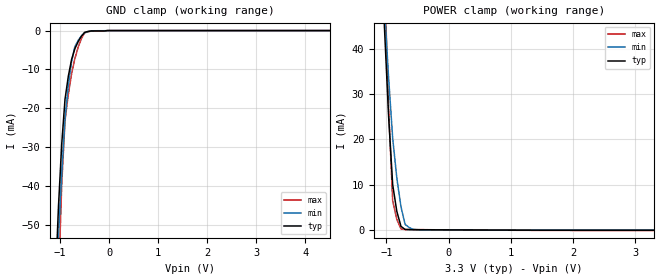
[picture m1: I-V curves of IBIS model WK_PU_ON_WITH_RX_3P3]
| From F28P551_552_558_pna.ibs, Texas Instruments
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|OPEN_DRAIN_MODE_3P3
|   Model Cell WK_PU_ON_WITH_RX_3P3
|WK_PU_ON_WITH_RX_3P3
[Model]   WK_PU_ON_WITH_RX_3P3
Model_type   Input
Polarity   Non-Inverting
Vinl =  0.8
Vinh =  2
C_comp   1.11773p   1.013376p   1.244487p
[Model Spec]
Vinl   0.8   0.8   0.8
Vinh   2   2   2
[Temperature Range]   25   155   -40
[Voltage Range]   3.3   2.97   3.63
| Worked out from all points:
|   GND clamp passes 1 mA (typ) near -0.54 V on its own axis
|   POWER clamp passes 1 mA (typ) near -0.77 V on its own axis
| Nom Voltages:
|   BIASFET=3.3, VDD=1.2, VDDS=3.3, VSS=0
| Min Voltages:
|   BIASFET=2.97, VDD=1.08, VDDS=2.97, VSS=0
| Max Voltages:
|   BIASFET=3.63, VDD=1.32, VDDS=3.63, VSS=0
[POWER_clamp]
|   voltage   I(typ)   I(min)   I(max)
-3.3V     1.132A     1.059A     1.769A
-1.033V   45.08mA    49.59mA    56.93mA
-966.7mV  25.39mA    33.9mA     27.23mA
-900mV    10.01mA    20.29mA    6.454mA
-833.3mV  4.092mA    11.48mA    2.326mA
-766.7mV  785.4uA    5.125mA    201.1uA
-700mV    89.29uA    1.212mA    78.7uA
-633.3mV  61.2uA     494uA      69.62uA
-566.7mV  44.07uA    99.73uA    61.24uA
3.3V      -85.93uA   -55.95uA   -137.9uA
[GND_clamp]
|   voltage   I(typ)   I(min)   I(max)
-3.3V     -1.198A    -966mA     -2.548A
-1.1V     -66.27mA   -70.87mA   -99.83mA
-1.033V   -45.41mA   -52.93mA   -65.12mA
-966.7mV  -29.23mA   -36.93mA   -39.6mA
-900mV    -17.72mA   -22.86mA   -23.27mA
-833.3mV  -11.83mA   -14.27mA   -16.55mA
-766.7mV  -7.493mA   -8.038mA   -11.21mA
-700mV    -4.704mA   -4.168mA   -7.263mA
-566.7mV  -1.465mA   -1.376mA   -2.095mA
-500mV    -469.8uA   -575.8uA   -591.3uA
-33.33mV  0A         0A         0A
6.6V      0A         0A         0A
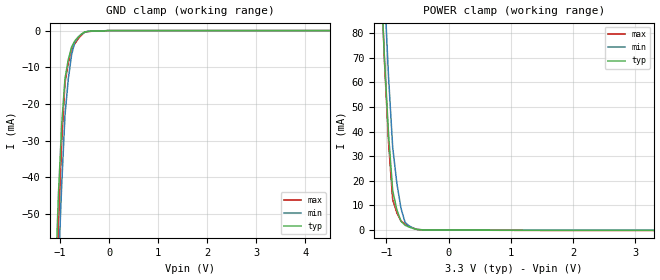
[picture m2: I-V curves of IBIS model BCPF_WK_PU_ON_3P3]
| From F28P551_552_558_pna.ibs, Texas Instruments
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|BCPF_WK_PD_ON_3P3; WEAK_PULLDOWN_ON
|   Model Cell BCPF_WK_PU_ON_3P3
|BCPF_WK_PU_ON_3P3
[Model]   BCPF_WK_PU_ON_3P3
Model_type   Input
Polarity   Non-Inverting
Vinl =  0.8
Vinh =  2
C_comp   1.21982p   0.982413p   1.3757p
[Model Spec]
Vinl   0.8   0.8   0.8
Vinh   2   2   2
[Temperature Range]   25   155   -40
[Voltage Range]   3.3   2.97   3.63
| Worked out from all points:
|   GND clamp passes 1 mA (typ) near -0.57 V on its own axis
|   POWER clamp passes 1 mA (typ) near -0.61 V on its own axis
| Nom Voltages:
|   BIASFET=3.3, VDD=1.2, VDDS=3.3, VSS=0
| Min Voltages:
|   BIASFET=2.97, VDD=1.08, VDDS=2.97, VSS=0
| Max Voltages:
|   BIASFET=3.63, VDD=1.32, VDDS=3.63, VSS=0
[POWER_clamp]
|   voltage   I(typ)   I(min)   I(max)
-3.3V     1.919A     2.431A     2.069A
-1.1V     109.8mA    140.8mA    113.2mA
-1.033V   70.21mA    98.04mA    69.24mA
-966.7mV  38.95mA    62.35mA    35.63mA
-900mV    16.03mA    33.73mA    12.36mA
-833.3mV  8.266mA    19.09mA    7.029mA
-766.7mV  3.571mA    8.879mA    3.722mA
-700mV    1.939mA    3.079mA    2.444mA
-566.7mV  603.9uA    711.2uA    759.2uA
-500mV    195.8uA    269.7uA    227.2uA
-366.7mV  40.85uA    44.56uA    53.2uA
3.3V      -108.8uA   -62.99uA   -174uA
[GND_clamp]
|   voltage   I(typ)   I(min)   I(max)
-3.3V     -1.48A     -1.41A     -2.182A
-1.1V     -69.91mA   -89.89mA   -82.68mA
-1.033V   -44.46mA   -64.18mA   -52.64mA
-966.7mV  -25.52mA   -41.89mA   -29.83mA
-900mV    -13.08mA   -23mA      -14.24mA
-833.3mV  -7.945mA   -13.29mA   -8.83mA
-766.7mV  -4.523mA   -6.66mA    -5.269mA
-700mV    -2.817mA   -3.105mA   -3.556mA
-566.7mV  -980.5uA   -1.002mA   -1.249mA
-500mV    -376.2uA   -438.1uA   -476.5uA
-33.33mV  0A         0A         0A
6.6V      0A         0A         0A
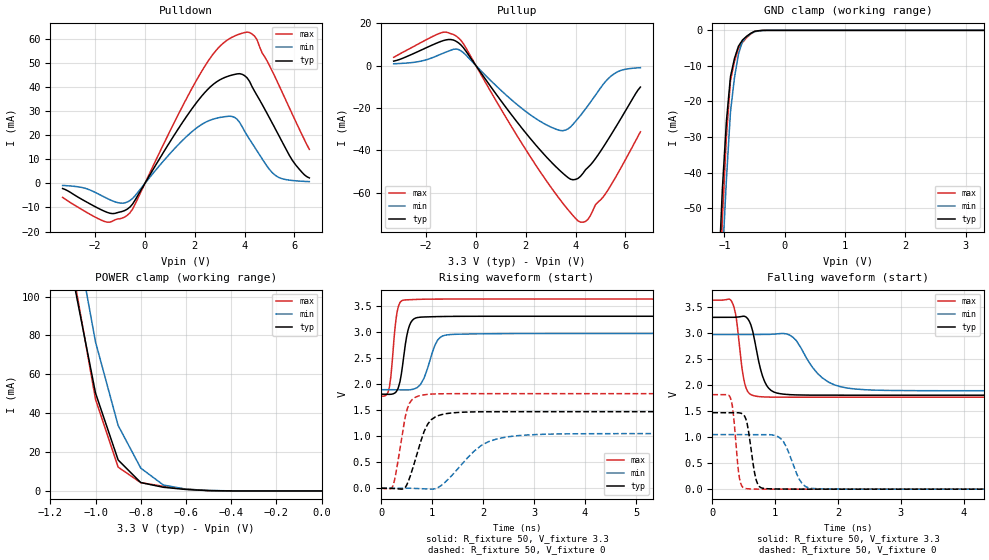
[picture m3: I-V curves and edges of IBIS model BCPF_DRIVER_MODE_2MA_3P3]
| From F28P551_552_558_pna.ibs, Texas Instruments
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|   Model Cell BCPF_DRIVER_MODE_2MA_3P3
|BCPF_DRIVER_MODE_2MA_3P3
[Model]   BCPF_DRIVER_MODE_2MA_3P3
Model_type   I/O
Polarity   Non-Inverting
Enable   Active-Low
Vinl =  0.8
Vinh =  2
Cref =  15.0000pF
Rref =  100.0000M
Vref =  0V
Vmeas =  1.65
C_comp   1.21982p   0.982413p   1.3757p
[Model Spec]
Vinl   0.8   0.8   0.8
Vinh   2   2   2
[Temperature Range]   25   155   -40
[Voltage Range]   3.3   2.97   3.63
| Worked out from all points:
|   slope of the pulldown table from 0 to 0.495 V, typ, clamps not added: 57.1 ohm
|   slope of the pullup table from 0 to 0.495 V, typ, clamps not added: 59.6 ohm
|   GND clamp passes 1 mA (typ) near -0.58 V on its own axis
|   POWER clamp passes 1 mA (typ) near -0.62 V on its own axis
|   rising waveform, R_fixture 50, V_fixture 3.3: 20-80 % time 140ps typ, 221ps min, 104ps max; typ from 1.8 V to 3.3 V
|   rising waveform, R_fixture 50, V_fixture 0: 20-80 % time 294ps typ, 647ps min, 192ps max; typ from 0 V to 1.47 V
|   falling waveform, R_fixture 50, V_fixture 3.3: 20-80 % time 172ps typ, 397ps min, 112ps max; typ from 3.3 V to 1.8 V
|   falling waveform, R_fixture 50, V_fixture 0: 20-80 % time 109ps typ, 211ps min, 80.2ps max; typ from 1.47 V to 0 V
| Nom Voltages:
|   BIASFET=3.3, VDD=1.2, VDDS=3.3, VSS=0
| Min Voltages:
|   BIASFET=2.97, VDD=1.08, VDDS=2.97, VSS=0
| Max Voltages:
|   BIASFET=3.63, VDD=1.32, VDDS=3.63, VSS=0
[POWER_clamp]
|   voltage   I(typ)   I(min)   I(max)
-3.3V     1.919A     2.431A     2.069A
-1.1V     109.8mA    140.8mA    113.1mA
-1.067V   89.98mA    119.4mA    91.15mA
-1.033V   70.17mA    98.03mA    69.15mA
-1V       50.36mA    76.65mA    47.16mA
-900mV    15.95mA    33.71mA    12.25mA
-800mV    4.313mA    11.75mA    4.256mA
-700mV    1.873mA    3.047mA    2.352mA
-600mV    751.5uA    902uA      945.8uA
-500mV    149.1uA    244.6uA    161.3uA
0V        284.5pA    4.537nA    258.9pA
[Pulldown]
|   voltage   I(typ)   I(min)   I(max)
-3.3V     -2.106mA   -829.9uA   -5.795mA
-1.6V     -11.66mA   -5.789mA   -15.87mA
-700mV    -10.64mA   -7.705mA   -13.21mA
-400mV    -7.072mA   -5.205mA   -8.811mA
1.4V      23.67mA    16.77mA    29.91mA
2.4V      37.79mA    25.3mA     48.71mA
3.5V      45.14mA    27.89mA    60.88mA
4.1V      44.01mA    20.04mA    63.01mA
4.5V      36.67mA    13.59mA    59.86mA
5.2V      23.42mA    3.673mA    44.88mA
5.9V      9.948mA    1.257mA    29.22mA
6.6V      2.302mA    773.2uA    14.19mA
[Pullup]
|   voltage   I(typ)   I(min)   I(max)
-3.3V     2.084mA    839.6uA    3.878mA
-1.4V     11.4mA     5.387mA    15.44mA
-700mV    10.72mA    7.564mA    13.05mA
1.5V      -24.35mA   -16.9mA    -30.22mA
2.8V      -42.78mA   -27.82mA   -53.93mA
3.6V      -51.98mA   -30.47mA   -66.68mA
3.9V      -53.94mA   -27.71mA   -70.9mA
4.2V      -52.27mA   -23.51mA   -73.96mA
4.5V      -48.09mA   -18.87mA   -72.58mA
4.8V      -43.92mA   -13.95mA   -65.69mA
5.4V      -33.13mA   -5.221mA   -56.87mA
6.6V      -10.17mA   -1.007mA   -31.3mA
[GND_clamp]
|   voltage   I(typ)   I(min)   I(max)
-3.3V     -1.48A     -1.41A     -2.182A
-1.1V     -69.89mA   -89.88mA   -82.66mA
-1.033V   -44.44mA   -64.17mA   -52.62mA
-966.7mV  -25.49mA   -41.87mA   -29.79mA
-900mV    -13.05mA   -22.99mA   -14.19mA
-833.3mV  -7.883mA   -13.27mA   -8.716mA
-766.7mV  -4.439mA   -6.634mA   -5.116mA
-700mV    -2.713mA   -3.07mA    -3.386mA
-566.7mV  -872.3uA   -953.1uA   -1.075mA
-500mV    -267.3uA   -387.3uA   -301.7uA
-300mV    -620.6nA   -5.397uA   -306.5nA
3.3V      284.5pA    7.662uA    205pA
[Ramp]
| variable   typ   min   max
dV/dt_f 0.91068086/0.17315914n 0.65955626/0.40063246n  1.1310004/0.11316852n
dV/dt_r 0.89181332/0.29713445n 0.63958487/0.65404172n  1.0978302/0.1928678n
R_load = 50
[Rising Waveform]
R_fixture = 50
V_fixture = 3.3
V_fixture_min = 2.97
V_fixture_max = 3.63
|   time   V(typ)   V(min)   V(max)
0s        1.805V     1.891V     1.767V
159.2ps   1.802V     1.891V     1.943V
276.6ps   1.837V     1.89V      3.145V
328.2ps   1.912V     1.889V     3.461V
472.6ps   2.765V     1.885V     3.614V
643.6ps   3.252V     1.905V     3.621V
841.1ps   3.286V     2.117V     3.627V
1.107ns   3.294V     2.844V     3.63V
1.375ns   3.298V     2.95V      3.63V
20.05ns   3.3V       2.97V      3.63V
[Rising Waveform]
R_fixture = 50
V_fixture = 0
V_fixture_min = 0
V_fixture_max = 0
|   time   V(typ)   V(min)   V(max)
0s        0V         0V         0V
184.2ps   0V         0V         -11.16mV
237ps     -4.349mV   0V         69.12mV
472.8ps   19.15mV    0V         1.38V
596.4ps   317.8mV    0V         1.693V
883.4ps   1.177V     -13.59mV   1.799V
1.17ns    1.409V     49.43mV    1.813V
1.96ns    1.467V     819.3mV    1.815V
2.852ns   1.469V     1.022V     1.815V
20.01ns   1.469V     1.048V     1.815V
[Falling Waveform]
R_fixture = 50
V_fixture = 3.3
V_fixture_min = 2.97
V_fixture_max = 3.63
|   time   V(typ)   V(min)   V(max)
0s        3.3V       2.97V      3.63V
325.7ps   3.3V       2.97V      3.557V
496.2ps   3.323V     2.97V      2.133V
562.6ps   3.274V     2.97V      1.875V
788.2ps   2.213V     2.97V      1.773V
1.061ns   1.837V     2.987V     1.767V
1.284ns   1.812V     2.916V     1.766V
1.847ns   1.805V     2.056V     1.767V
2.418ns   1.805V     1.911V     1.767V
20.05ns   1.805V     1.891V     1.767V
[Falling Waveform]
R_fixture = 50
V_fixture = 0
V_fixture_min = 0
V_fixture_max = 0
|   time   V(typ)   V(min)   V(max)
0s        1.469V     1.048V     1.815V
284.2ps   1.469V     1.048V     1.765V
333.9ps   1.47V      1.048V     1.447V
433.4ps   1.465V     1.048V     195.6mV
577.2ps   1.097V     1.049V     5.968mV
697.4ps   174.8mV    1.049V     0V
894.6ps   7.295mV    1.048V     0V
1.09ns    2.604mV    969.1mV    0V
1.63ns    0V         9.869mV    0V
20.01ns   0V         0V         0V
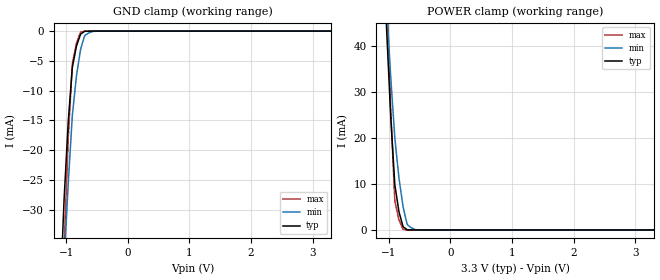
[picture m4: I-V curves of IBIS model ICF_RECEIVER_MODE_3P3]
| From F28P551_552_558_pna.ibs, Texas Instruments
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|ICF_WK_PD_ON_3P3; WEAK_PULLDOWN_ON
|   Model Cell ICF_RECEIVER_MODE_3P3
|ICF_RECEIVER_MODE_3P3
[Model]   ICF_RECEIVER_MODE_3P3
Model_type   Input
Polarity   Non-Inverting
Vinl =  0.8
Vinh =  2
C_comp   0.705929p   0.524756p   0.819798p
[Model Spec]
Vinl   0.8   0.8   0.8
Vinh   2   2   2
[Temperature Range]   25   155   -40
[Voltage Range]   3.3   2.97   3.63
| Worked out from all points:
|   GND clamp passes 1 mA (typ) near -0.78 V on its own axis
|   POWER clamp passes 1 mA (typ) near -0.77 V on its own axis
| Nom Voltages:
|   BIASFET=3.3, VDD=1.2, VDDS=3.3, VSS=0
| Min Voltages:
|   BIASFET=2.97, VDD=1.08, VDDS=2.97, VSS=0
| Max Voltages:
|   BIASFET=3.63, VDD=1.32, VDDS=3.63, VSS=0
[POWER_clamp]
|   voltage   I(typ)   I(min)   I(max)
-3.3V     1.081A     1.025A     1.649A
-1.033V   43.59mA    48.4mA     54mA
-966.7mV  24.68mA    33.19mA    26.05mA
-900mV    9.809mA    19.96mA    6.269mA
-833.3mV  3.983mA    11.32mA    2.208mA
-766.7mV  725.6uA    5.059mA    119.3uA
-700mV    36.21uA    1.184mA    3.804uA
-633.3mV  13.05uA    468.6uA    1.632uA
-566.7mV  1.004uA    77.01uA    376.5nA
3.3V      -122.3pA   -178.5nA   -103.6pA
[GND_clamp]
|   voltage   I(typ)   I(min)   I(max)
-3.3V     -921.9mA   -819.9mA   -1.722A
-1.1V     -45.04mA   -53.69mA   -60.94mA
-1.033V   -28.27mA   -38.87mA   -36.58mA
-966.7mV  -15.3mA    -25.7mA    -18.11mA
-900mV    -6.119mA   -14.19mA   -5.524mA
-833.3mV  -2.544mA   -7.576mA   -2.031mA
-766.7mV  -516.7uA   -3.097mA   -192.4uA
-700mV    -37.6uA    -751uA     -9.113uA
-566.7mV  -1.793uA   -61.77uA   -1.3uA
-500mV    -316.1nA   -8.977uA   -253.9nA
3.3V      210.2pA    137.5nA    178.6pA
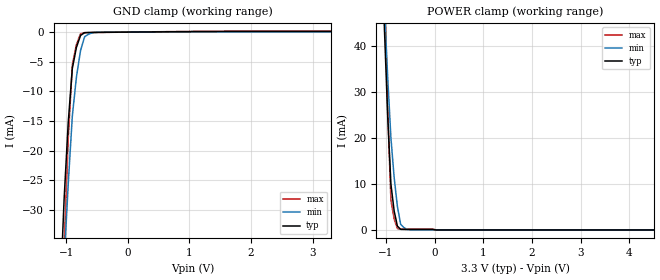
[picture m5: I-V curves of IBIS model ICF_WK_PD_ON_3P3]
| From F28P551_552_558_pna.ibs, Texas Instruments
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|   Model Cell ICF_WK_PD_ON_3P3
|ICF_WK_PD_ON_3P3
[Model]   ICF_WK_PD_ON_3P3
Model_type   Input
Polarity   Non-Inverting
Vinl =  0.8
Vinh =  2
C_comp   0.705929p   0.524756p   0.819798p
[Model Spec]
Vinl   0.8   0.8   0.8
Vinh   2   2   2
[Temperature Range]   25   155   -40
[Voltage Range]   3.3   2.97   3.63
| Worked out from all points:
|   GND clamp passes 1 mA (typ) near -0.78 V on its own axis
|   POWER clamp passes 1 mA (typ) near -0.77 V on its own axis
| Nom Voltages:
|   BIASFET=3.3, VDD=1.2, VDDS=3.3, VSS=0
| Min Voltages:
|   BIASFET=2.97, VDD=1.08, VDDS=2.97, VSS=0
| Max Voltages:
|   BIASFET=3.63, VDD=1.32, VDDS=3.63, VSS=0
[POWER_clamp]
|   voltage   I(typ)   I(min)   I(max)
-3.3V     1.081A     1.025A     1.649A
-1.033V   43.65mA    48.41mA    54.13mA
-966.7mV  24.75mA    33.21mA    26.21mA
-900mV    9.902mA    19.98mA    6.441mA
-833.3mV  4.083mA    11.35mA    2.383mA
-766.7mV  830uA      5.098mA    296uA
-700mV    141.9uA    1.23mA     181.2uA
-633.3mV  119.3uA    517.3uA    179.8uA
-566.7mV  107.7uA    127.2uA    179.1uA
-500mV    107.1uA    59.96uA    178.9uA
33.33mV   0A         0A         0A
6.6V      0A         0A         0A
[GND_clamp]
|   voltage   I(typ)   I(min)   I(max)
-3.3V     -921.9mA   -819.9mA   -1.722A
-1.1V     -45.05mA   -53.69mA   -60.95mA
-1.033V   -28.29mA   -38.87mA   -36.59mA
-966.7mV  -15.32mA   -25.71mA   -18.12mA
-900mV    -6.141mA   -14.2mA    -5.548mA
-833.3mV  -2.58mA    -7.589mA   -2.09mA
-766.7mV  -565uA     -3.114mA   -273.6uA
-700mV    -96.68uA   -773.5uA   -98.02uA
-566.7mV  -52.72uA   -88.84uA   -76.49uA
-500mV    -45.74uA   -34.15uA   -67.39uA
3.3V      106.7uA    51.11uA    177.8uA
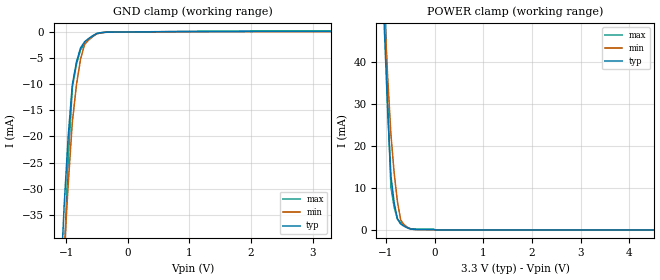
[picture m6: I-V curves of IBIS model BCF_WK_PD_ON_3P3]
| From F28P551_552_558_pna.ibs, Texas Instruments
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|   Model Cell BCF_WK_PD_ON_3P3
|BCF_WK_PD_ON_3P3
[Model]   BCF_WK_PD_ON_3P3
Model_type   Input
Polarity   Non-Inverting
Vinl =  0.8
Vinh =  2
C_comp   1.28683p   1.00698p   1.46241p
[Model Spec]
Vinl   0.8   0.8   0.8
Vinh   2   2   2
[Temperature Range]   25   155   -40
[Voltage Range]   3.3   2.97   3.63
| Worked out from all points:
|   GND clamp passes 1 mA (typ) near -0.60 V on its own axis
|   POWER clamp passes 1 mA (typ) near -0.65 V on its own axis
| Nom Voltages:
|   BIASFET=3.3, VDD=1.2, VDDS=3.3, VSS=0
| Min Voltages:
|   BIASFET=2.97, VDD=1.08, VDDS=2.97, VSS=0
| Max Voltages:
|   BIASFET=3.63, VDD=1.32, VDDS=3.63, VSS=0
[POWER_clamp]
|   voltage   I(typ)   I(min)   I(max)
-3.3V     1.107A     1.023A     1.677A
-1.033V   47.42mA    52.06mA    58.71mA
-966.7mV  28.13mA    36.41mA    30.42mA
-900mV    12.85mA    22.7mA     10.2mA
-833.3mV  6.476mA    13.54mA    5.424mA
-766.7mV  2.66mA     6.776mA    2.62mA
-700mV    1.404mA    2.41mA     1.782mA
-566.7mV  517.2uA    574.5uA    683.4uA
-500mV    228.9uA    248.6uA    311.4uA
-366.7mV  112.5uA    73.48uA    183.4uA
33.33mV   0A         0A         0A
6.6V      0A         0A         0A
[GND_clamp]
|   voltage   I(typ)   I(min)   I(max)
-3.3V     -944.5mA   -826.8mA   -1.736A
-1.1V     -50.7mA    -57.86mA   -68.89mA
-1.033V   -33.48mA   -42.7mA    -43.82mA
-966.7mV  -19.95mA   -29.18mA   -24.41mA
-900mV    -10.1mA    -17.28mA   -10.65mA
-833.3mV  -5.796mA   -10.18mA   -6.165mA
-766.7mV  -3.052mA   -5.196mA   -3.386mA
-700mV    -1.868mA   -2.325mA   -2.314mA
-566.7mV  -694uA     -751.1uA   -858.4uA
-500mV    -270.4uA   -343.4uA   -322uA
-300mV    -27.35uA   -20.01uA   -40.48uA
3.3V      105.9uA    57.28uA    177.6uA
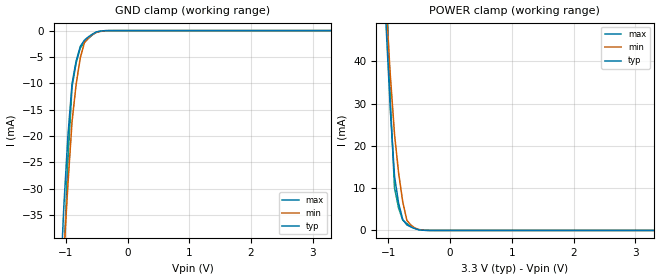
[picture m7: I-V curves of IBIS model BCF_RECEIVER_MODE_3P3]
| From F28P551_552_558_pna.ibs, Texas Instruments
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|   Model Cell BCF_RECEIVER_MODE_3P3
|BCF_RECEIVER_MODE_3P3
[Model]   BCF_RECEIVER_MODE_3P3
Model_type   Input
Polarity   Non-Inverting
Vinl =  0.8
Vinh =  2
C_comp   1.28683p   1.00698p   1.46241p
[Model Spec]
Vinl   0.8   0.8   0.8
Vinh   2   2   2
[Temperature Range]   25   155   -40
[Voltage Range]   3.3   2.97   3.63
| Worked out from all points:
|   GND clamp passes 1 mA (typ) near -0.61 V on its own axis
|   POWER clamp passes 1 mA (typ) near -0.66 V on its own axis
| Nom Voltages:
|   BIASFET=3.3, VDD=1.2, VDDS=3.3, VSS=0
| Min Voltages:
|   BIASFET=2.97, VDD=1.08, VDDS=2.97, VSS=0
| Max Voltages:
|   BIASFET=3.63, VDD=1.32, VDDS=3.63, VSS=0
[POWER_clamp]
|   voltage   I(typ)   I(min)   I(max)
-3.3V     1.107A     1.023A     1.677A
-1.033V   47.37mA    52.05mA    58.58mA
-966.7mV  28.06mA    36.39mA    30.27mA
-900mV    12.76mA    22.68mA    10.02mA
-833.3mV  6.376mA    13.51mA    5.25mA
-766.7mV  2.556mA    6.737mA    2.444mA
-700mV    1.299mA    2.365mA    1.605mA
-633.3mV  803.5uA    1.247mA    995.7uA
-566.7mV  411.4uA    524.7uA    505.1uA
-500mV    122.7uA    198.2uA    132.8uA
-366.7mV  6.325uA    22.93uA    4.864uA
3.3V      -325.7pA   -11.09uA   -316.3pA
[GND_clamp]
|   voltage   I(typ)   I(min)   I(max)
-3.3V     -944.5mA   -826.8mA   -1.736A
-1.1V     -50.69mA   -57.85mA   -68.88mA
-1.033V   -33.47mA   -42.7mA    -43.81mA
-966.7mV  -19.93mA   -29.17mA   -24.39mA
-900mV    -10.08mA   -17.27mA   -10.63mA
-833.3mV  -5.761mA   -10.17mA   -6.106mA
-766.7mV  -3.004mA   -5.18mA    -3.306mA
-700mV    -1.81mA    -2.303mA   -2.225mA
-566.7mV  -643.8uA   -724.5uA   -783.6uA
-500mV    -225.6uA   -318.6uA   -255.2uA
-300mV    -598.1nA   -5.157uA   -296.9nA
3.3V      319.4pA    6.726uA    227.5pA
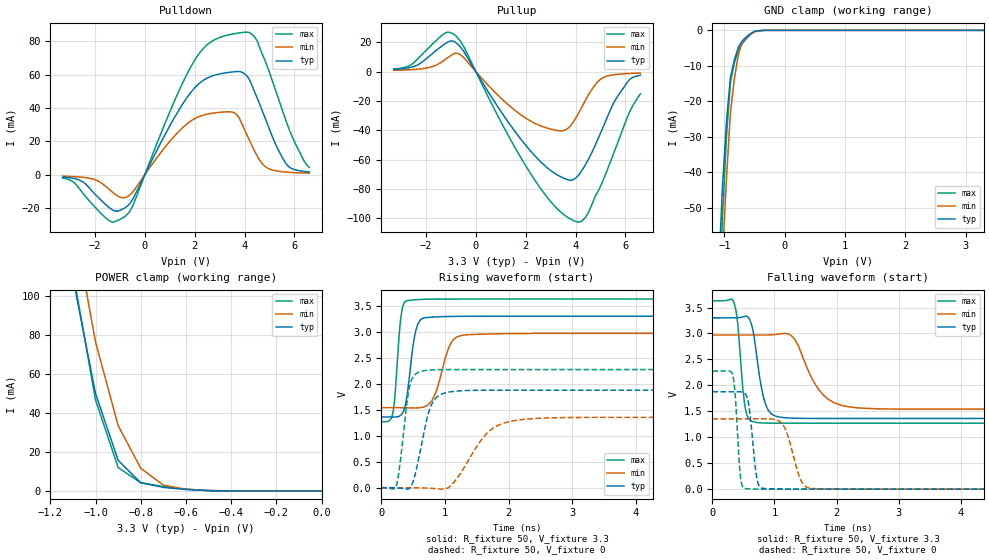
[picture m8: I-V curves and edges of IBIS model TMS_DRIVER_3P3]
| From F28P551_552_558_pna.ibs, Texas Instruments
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|   Model Cell TMS_DRIVER_3P3
|TMS_DRIVER_3P3
[Model]   TMS_DRIVER_3P3
Model_type   I/O
Polarity   Non-Inverting
Enable   Active-Low
Vinl =  0.8
Vinh =  2
Cref =  15.0000pF
Rref =  100.0000M
Vref =  0V
Vmeas =  1.65
C_comp   1.26765p   1.03155p   1.45072p
[Model Spec]
Vinl   0.8   0.8   0.8
Vinh   2   2   2
[Temperature Range]   25   155   -40
[Voltage Range]   3.3   2.97   3.63
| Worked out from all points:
|   slope of the pulldown table from 0 to 0.495 V, typ, clamps not added: 33.1 ohm
|   slope of the pullup table from 0 to 0.495 V, typ, clamps not added: 35.9 ohm
|   GND clamp passes 1 mA (typ) near -0.57 V on its own axis
|   POWER clamp passes 1 mA (typ) near -0.63 V on its own axis
|   rising waveform, R_fixture 50, V_fixture 3.3: 20-80 % time 122ps typ, 203ps min, 84.7ps max; typ from 1.36 V to 3.3 V
|   rising waveform, R_fixture 50, V_fixture 0: 20-80 % time 203ps typ, 451ps min, 131ps max; typ from 0 V to 1.88 V
|   falling waveform, R_fixture 50, V_fixture 3.3: 20-80 % time 154ps typ, 366ps min, 98.3ps max; typ from 3.3 V to 1.36 V
|   falling waveform, R_fixture 50, V_fixture 0: 20-80 % time 95ps typ, 193ps min, 68.9ps max; typ from 1.88 V to 0 V
| Nom Voltages:
|   BIASFET=3.3, VDD=1.2, VDDS=3.3, VSS=0
| Min Voltages:
|   BIASFET=2.97, VDD=1.08, VDDS=2.97, VSS=0
| Max Voltages:
|   BIASFET=3.63, VDD=1.32, VDDS=3.63, VSS=0
[POWER_clamp]
|   voltage   I(typ)   I(min)   I(max)
-3.3V     1.919A     2.431A     2.069A
-1.1V     109.6mA    140.7mA    112.7mA
-1.067V   89.74mA    119.3mA    90.7mA
-1.033V   69.92mA    97.93mA    68.74mA
-1V       50.1mA     76.55mA    46.78mA
-900mV    15.74mA    33.61mA    12.02mA
-800mV    4.204mA    11.66mA    4.167mA
-700mV    1.814mA    2.972mA    2.293mA
-600mV    716.5uA    858.2uA    909.7uA
-500mV    138.9uA    227uA      152.2uA
0V        307.5pA    4.709nA    280.9pA
[Pulldown]
|   voltage   I(typ)   I(min)   I(max)
-3.3V     -1.487mA   -924.2uA   -2.099mA
-2.5V     -4.195mA   -1.617mA   -10.9mA
-1.4V     -20.16mA   -9.286mA   -27.98mA
-800mV    -19.96mA   -13.84mA   -25.2mA
-500mV    -15.16mA   -10.67mA   -19.2mA
1.1V      31.93mA    21.68mA    41.17mA
2.1V      53.66mA    34.39mA    71.06mA
3.5V      61.62mA    37.57mA    84.37mA
4.1V      59.16mA    23.66mA    85.59mA
4.5V      46.26mA    11.37mA    80.54mA
5.6V      8.041mA    1.603mA    35.1mA
6.6V      1.614mA    875.6uA    4.352mA
[Pullup]
|   voltage   I(typ)   I(min)   I(max)
-3.3V     1.549mA    921.4uA    1.826mA
-2.6V     3.01mA     1.383mA    4.759mA
-1.8V     11.56mA    3.248mA    17.91mA
-900mV    20.89mA    12.19mA    25.83mA
-500mV    14.17mA    9.801mA    17.58mA
2.4V      -58.06mA   -35.54mA   -74.92mA
3.5V      -72.55mA   -40.3mA    -97.22mA
4.1V      -71.09mA   -28.89mA   -102.8mA
4.4V      -63.3mA    -19.35mA   -99.38mA
5V        -41.98mA   -5.171mA   -78.29mA
5.8V      -13.95mA   -1.597mA   -43.52mA
6.6V      -2.434mA   -958.5uA   -15.11mA
[GND_clamp]
|   voltage   I(typ)   I(min)   I(max)
-3.3V     -1.48A     -1.41A     -2.182A
-1.1V     -69.78mA   -89.94mA   -82.82mA
-1.033V   -44.53mA   -64.24mA   -52.89mA
-966.7mV  -25.7mA    -41.95mA   -30.12mA
-900mV    -13.3mA    -23.09mA   -14.49mA
-833.3mV  -8.122mA   -13.37mA   -9.07mA
-766.7mV  -4.654mA   -6.724mA   -5.455mA
-700mV    -2.893mA   -3.151mA   -3.644mA
-566.7mV  -921uA     -990.1uA   -1.143mA
-500mV    -277.1uA   -399.9uA   -314.1uA
-300mV    -639.2nA   -5.487uA   -319.4nA
3.3V      307.5pA    6.987uA    225.6pA
[Ramp]
| variable   typ   min   max
dV/dt_f   1.1835/0.15607984n 0.87618775/0.36982389n   1.435287/99.520914p
dV/dt_r  1.1424406/0.20599639n 0.82935554/0.45734753n  1.3784801/0.13260876n
R_load = 50
[Rising Waveform]
R_fixture = 50
V_fixture = 3.3
V_fixture_min = 2.97
V_fixture_max = 3.63
|   time   V(typ)   V(min)   V(max)
0s        1.362V     1.541V     1.271V
175.5ps   1.359V     1.541V     1.405V
319.9ps   1.412V     1.54V      3.387V
437.5ps   2.093V     1.536V     3.606V
519.7ps   2.891V     1.533V     3.615V
601.4ps   3.211V     1.537V     3.622V
803.1ps   3.282V     1.688V     3.629V
1.102ns   3.296V     2.799V     3.63V
1.391ns   3.299V     2.947V     3.63V
20.01ns   3.3V       2.97V      3.63V
[Rising Waveform]
R_fixture = 50
V_fixture = 0
V_fixture_min = 0
V_fixture_max = 0
|   time   V(typ)   V(min)   V(max)
0s        0V         0V         0V
240.4ps   -3.624mV   0V         54.38mV
402.5ps   -26.86mV   0V         1.634V
478.2ps   45.32mV    0V         2.08V
759.5ps   1.506V     -10.17mV   2.265V
869.8ps   1.743V     -20.86mV   2.271V
1.103ns   1.848V     49.84mV    2.274V
1.76ns    1.876V     1.151V     2.274V
2.419ns   1.876V     1.333V     2.274V
20.05ns   1.876V     1.354V     2.274V
[Falling Waveform]
R_fixture = 50
V_fixture = 3.3
V_fixture_min = 2.97
V_fixture_max = 3.63
|   time   V(typ)   V(min)   V(max)
0s        3.3V       2.97V      3.63V
346.5ps   3.299V     2.97V      3.597V
534ps     3.333V     2.97V      1.533V
633.9ps   3.159V     2.97V      1.309V
743.6ps   2.299V     2.969V     1.281V
999.6ps   1.415V     2.978V     1.271V
1.33ns    1.367V     2.879V     1.271V
1.865ns   1.363V     1.731V     1.271V
2.459ns   1.362V     1.558V     1.271V
20.01ns   1.362V     1.541V     1.271V
[Falling Waveform]
R_fixture = 50
V_fixture = 0
V_fixture_min = 0
V_fixture_max = 0
|   time   V(typ)   V(min)   V(max)
0s        1.876V     1.354V     2.274V
319.7ps   1.877V     1.354V     2.227V
460.5ps   1.874V     1.354V     160mV
558.4ps   1.768V     1.354V     8.786mV
720.4ps   178.9mV    1.355V     0V
873ps     9.74mV     1.357V     0V
1.133ns   2.145mV    1.247V     0V
1.437ns   0V         141.2mV    0V
1.635ns   0V         10.9mV     0V
20.05ns   0V         0V         0V
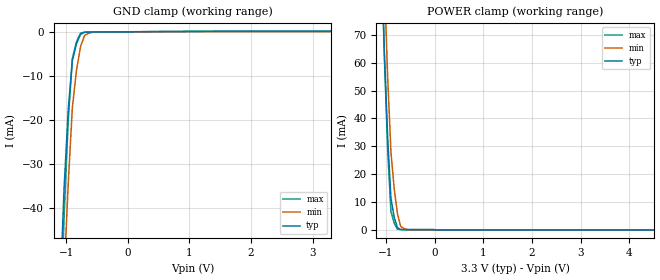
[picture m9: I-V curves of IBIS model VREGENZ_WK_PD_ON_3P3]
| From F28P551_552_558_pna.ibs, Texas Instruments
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|VREGENZ_WK_PD_OFF_3P3; WEAK_PULLDOWN_OFF
|   Model Cell VREGENZ_WK_PD_ON_3P3
|VREGENZ_WK_PD_ON_3P3
[Model]   VREGENZ_WK_PD_ON_3P3
Model_type   Input
Polarity   Non-Inverting
Vinl =  0.8
Vinh =  2
C_comp   1.1812p   1.10922p   1.21731p
[Model Spec]
Vinl   0.8   0.8   0.8
Vinh   2   2   2
[Temperature Range]   25   155   -40
[Voltage Range]   3.3   2.97   3.63
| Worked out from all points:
|   GND clamp passes 1 mA (typ) near -0.78 V on its own axis
|   POWER clamp passes 1 mA (typ) near -0.77 V on its own axis
| Nom Voltages:
|   BIASFET=3.3, VDD=1.2, VDDS=3.3, VSS=0
| Min Voltages:
|   BIASFET=2.97, VDD=1.08, VDDS=2.97, VSS=0
| Max Voltages:
|   BIASFET=3.63, VDD=1.32, VDDS=3.63, VSS=0
[POWER_clamp]
|   voltage   I(typ)   I(min)   I(max)
-3.3V     1.823A     2.351A     1.96A
-1.1V     100.7mA    129.7mA    104mA
-1.033V   62.86mA    88.78mA    61.4mA
-966.7mV  33.07mA    54.88mA    28.94mA
-900mV    11.35mA    27.98mA    6.644mA
-833.3mV  4.58mA     14.87mA    2.443mA
-766.7mV  839.1uA    5.967mA    285.6uA
-700mV    131.4uA    1.272mA    170.7uA
-566.7mV  97.23uA    120.8uA    168.7uA
-500mV    96.59uA    53.18uA    168.7uA
6.6V      0A         0A         0A
[GND_clamp]
|   voltage   I(typ)   I(min)   I(max)
-3.3V     -1.38A     -1.323A    -2.074A
-1.1V     -59.6mA    -79.12mA   -70.72mA
-1.033V   -35.49mA   -55.25mA   -41.83mA
-966.7mV  -17.83mA   -34.66mA   -20.31mA
-900mV    -6.6mA     -17.33mA   -6.147mA
-833.3mV  -2.744mA   -8.865mA   -2.295mA
-766.7mV  -575.7uA   -3.351mA   -279.2uA
-700mV    -96.31uA   -787uA     -98.86uA
-566.7mV  -52.15uA   -88.17uA   -76.87uA
3.3V      96.5uA     44.35uA    168.5uA
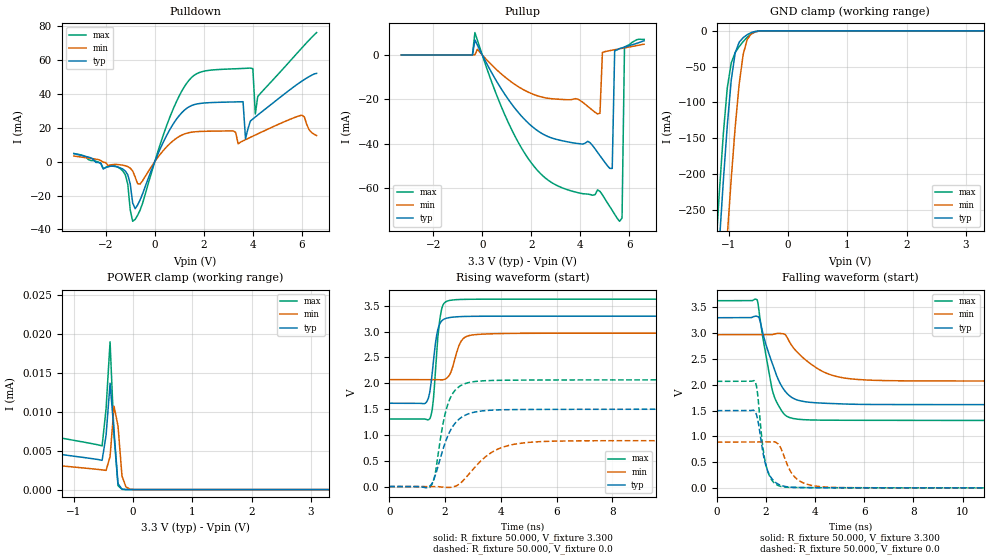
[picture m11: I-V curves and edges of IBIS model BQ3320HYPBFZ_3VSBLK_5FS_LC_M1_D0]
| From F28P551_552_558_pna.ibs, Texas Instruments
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|   Model BQ3320HYPBFZ_3VSBLK_5FS_LC_M1_D0
[Model] BQ3320HYPBFZ_3VSBLK_5FS_LC_M1_D0
Model_type I/O
Polarity   Non-Inverting
Enable   Active-Low
Vinl =  0.990V
Vinh =  2.310V
Vmeas =  1.650V
C_comp   3.578pF   3.271pF   3.695pF
[Model Spec]
Vinh   2.310V   2.079V   2.541V
Vinl   0.990V   0.891V   1.089V
Vmeas   1.650V   1.485V   1.815V
[Temperature Range]   25.000   0.155k   -40.000
[Voltage Range]   3.300V   2.970V   3.630V
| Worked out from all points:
|   slope of the pulldown table from 0 to 0.495 V, typ, clamps not added: 31.3 ohm
|   slope of the pullup table from 0 to 0.495 V, typ, clamps not added: 48.7 ohm
|   GND clamp passes 1 mA (typ) near -0.56 V on its own axis
|   rising waveform, R_fixture 50.000, V_fixture 3.300: 20-80 % time 224ps typ, 316ps min, 199ps max; typ from 1.61 V to 3.3 V
|   rising waveform, R_fixture 50.000, V_fixture 0.0: 20-80 % time 621ps typ, 1.08ns min, 444ps max; typ from 0 V to 1.5 V
|   falling waveform, R_fixture 50.000, V_fixture 3.300: 20-80 % time 774ps typ, 1.33ns min, 544ps max; typ from 3.3 V to 1.61 V
|   falling waveform, R_fixture 50.000, V_fixture 0.0: 20-80 % time 382ps typ, 583ps min, 317ps max; typ from 1.5 V to 0 V
[Pulldown]
|Voltage   I(typ)   I(min)   I(max)
-3.3V     4.876mA    3.346mA    4.743mA
-1.3V     -4.38mA    -2.076mA   -5.509mA
-900mV    -24.41mA   -5.518mA   -35.22mA
-600mV    -22.67mA   -13.22mA   -28.7mA
600mV     18.59mA    10.46mA    25.74mA
1.5V      33.16mA    17.43mA    49.73mA
3.6V      35.43mA    12.3mA     55.09mA
3.7V      13.6mA     13mA       55.16mA
4V        25.24mA    15.07mA    54.96mA
4.1V      26.41mA    15.75mA    28.12mA
6V        47.6mA     27.49mA    67.23mA
6.6V      52.19mA    15.47mA    76.29mA
[Pullup]
|Voltage   I(typ)   I(min)   I(max)
-3.3V     91.12nA    732.4nA    263.9pA
-300mV    6.771mA    40uA       10.12mA
2.1V      -32.9mA    -17.84mA   -50.16mA
4.7V      -43.94mA   -26.64mA   -60.94mA
4.8V      -45.49mA   -26.32mA   -61.57mA
4.9V      -46.98mA   1.131mA    -63.18mA
5.3V      -51.23mA   2.168mA    -70.17mA
5.4V      1.935mA    2.379mA    -71.96mA
5.6V      2.889mA    2.796mA    -75.11mA
5.7V      3.22mA     3.002mA    -73.66mA
5.8V      3.55mA     3.206mA    3.605mA
6.6V      6.407mA    4.882mA    7.034mA
[GND_clamp]
|Voltage   I(typ)   I(min)   I(max)
-3.3V     -3.505A    -3.628A    -3.476A
-1.223V   -386.4mA   -550.8mA   -315.4mA
-1.156V   -296.3mA   -460mA     -226.1mA
-1.089V   -210.5mA   -371.5mA   -144.6mA
-1.022V   -132.4mA   -286.5mA   -79.77mA
-955mV    -68.78mA   -206.3mA   -44.76mA
-888mV    -30.47mA   -133.9mA   -30.31mA
-821mV    -15.84mA   -73.99mA   -22.01mA
-754mV    -9.591mA   -32.92mA   -15.01mA
-687mV    -5.432mA   -12.28mA   -9.043mA
-620mV    -2.525mA   -4.288mA   -4.466mA
3.3V      0A         0A         0A
[POWER_clamp]
|Voltage   I(typ)   I(min)   I(max)
-3.3V     514.6uA    72.31mA    9.49uA
-3.266V   143.9uA    52.63mA    9.442uA
-3.132V   7.182uA    5.855mA    9.258uA
-2.931V   6.231uA    34.42uA    8.984uA
-2.864V   6.164uA    9.16uA     8.891uA
-2.73V    6.03uA     4.29uA     8.708uA
-519mV    3.757uA    2.535uA    5.613uA
-385mV    13.66uA    4.234uA    18.99uA
-318mV    7.479uA    10.7uA     6.925uA
-251mV    757.2nA    8.165uA    518.6nA
-184mV    65.19nA    1.742uA    33.01nA
3.3V      0A         0A         0A
[Ramp]
| variable   typ   min   max
dV/dt_r   0.899/0.621n   0.533/1.081n   1.240/0.444n
dV/dt_f   1.012/0.774n   0.539/1.325n   1.393/0.545n
R_load = 50.000
[Rising Waveform]
R_fixture= 50.000
V_fixture= 3.300
V_fixture_min= 2.970
V_fixture_max= 3.630
|time   V(typ)   V(min)   V(max)
0s        1.613V     2.072V     1.307V
1.271ns   1.608V     2.072V     1.308V
1.464ns   1.859V     2.072V     1.324V
1.578ns   2.383V     2.072V     1.649V
1.736ns   3.022V     2.069V     2.844V
1.836ns   3.173V     2.067V     3.316V
2.198ns   3.276V     2.199V     3.608V
2.607ns   3.293V     2.836V     3.625V
3.227ns   3.299V     2.948V     3.629V
25ns      3.3V       2.97V      3.63V
[Rising Waveform]
R_fixture= 50.000
V_fixture= 0.0
V_fixture_min= 0.0
V_fixture_max= 0.0
|time   V(typ)   V(min)   V(max)
0s        2.241uV    2.641uV    1.891uV
1.484ns   22.75mV    707.2uV    -886.1uV
1.643ns   196.8mV    1.047mV    231.9mV
1.924ns   714.2mV    -11.69mV   1.203V
2.148ns   1.037V     -17.68mV   1.661V
2.468ns   1.288V     30.93mV    1.92V
2.988ns   1.433V     322.9mV    2.028V
3.938ns   1.485V     735.2mV    2.058V
5.418ns   1.494V     870.1mV    2.064V
25ns      1.498V     888.2mV    2.066V
[Falling Waveform]
R_fixture= 50.000
V_fixture= 3.300
V_fixture_min= 2.970
V_fixture_max= 3.630
|time   V(typ)   V(min)   V(max)
0s        3.3V       2.97V      3.63V
1.642ns   3.327V     2.97V      3.646V
1.742ns   3.277V     2.97V      3.352V
2.142ns   2.574V     2.969V     2.18V
2.304ns   2.351V     2.979V     1.823V
2.774ns   1.878V     2.977V     1.416V
3.118ns   1.736V     2.716V     1.345V
4.338ns   1.642V     2.25V      1.313V
5.85ns    1.619V     2.099V     1.31V
25ns      1.613V     2.072V     1.308V
[Falling Waveform]
R_fixture= 50.000
V_fixture= 0.0
V_fixture_min= 0.0
V_fixture_max= 0.0
|time   V(typ)   V(min)   V(max)
0s        1.498V     888.2mV    2.066V
1.559ns   1.479V     888.2mV    2.065V
1.665ns   1.33V      888.1mV    1.818V
1.877ns   692.6mV    888mV      786.7mV
2.028ns   388.3mV    887.9mV    394.3mV
2.276ns   157.8mV    893.5mV    127.9mV
2.677ns   38.96mV    692.7mV    19.83mV
3.259ns   8.158mV    172mV      6.326mV
4.419ns   2.473mV    15.94mV    3.007mV
25ns      25.95uV    128.6uV    16.73uV
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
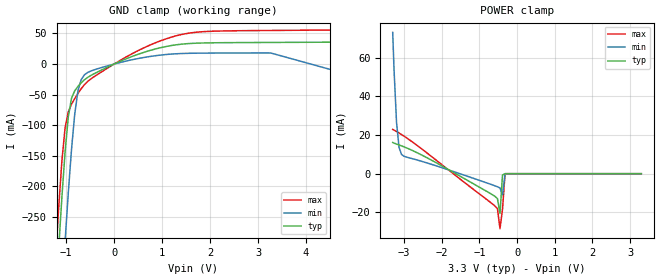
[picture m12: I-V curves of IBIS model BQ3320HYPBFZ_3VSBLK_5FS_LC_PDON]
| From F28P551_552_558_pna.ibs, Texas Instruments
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|   Model BQ3320HYPBFZ_3VSBLK_5FS_LC_PDON
[Model] BQ3320HYPBFZ_3VSBLK_5FS_LC_PDON
Model_type Input
Polarity   Non-Inverting
Enable   Active-High
Vinl =  0.990V
Vinh =  2.310V
C_comp   3.681pF   3.377pF   3.769pF
[Model Spec]
Vinh   2.310V   2.079V   2.541V
Vinl   0.990V   0.891V   1.089V
[Temperature Range]   25.000   0.155k   -40.000
[Voltage Range]   3.300V   2.970V   3.630V
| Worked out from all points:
|   GND clamp passes 1 mA (typ) near -0.03 V on its own axis
|   POWER clamp passes 1 mA (typ) near -0.39 V on its own axis
[GND_clamp]
|Voltage   I(typ)   I(min)   I(max)
-3.3V     -3.506A    -3.628A    -3.477A
-1.223V   -391.8mA   -553.3mA   -322.8mA
-1.156V   -302.6mA   -462.7mA   -235.9mA
-1.022V   -143.9mA   -290.1mA   -104.5mA
-955mV    -86.64mA   -210.8mA   -78.43mA
-888mV    -55.98mA   -139.8mA   -65.59mA
-754mV    -36.56mA   -44.04mA   -48.08mA
-620mV    -25.82mA   -17.73mA   -33.83mA
-151mV    -5.549mA   -3.243mA   -7.346mA
1.39V     32.37mA    17.14mA    48mA
3.266V    35.31mA    18.07mA    54.88mA
6.6V      36.47mA    -54.22mA   56.8mA
[POWER_clamp]
|Voltage   I(typ)   I(min)   I(max)
-3.3V     16.16mA    73.08mA    22.92mA
-3.266V   15.82mA    54.44mA    22.56mA
-3.199V   15.34mA    26.69mA    21.82mA
-3.132V   14.88mA    13.57mA    21.04mA
-3.065V   14.39mA    9.909mA    20.23mA
-2.998V   13.87mA    8.983mA    19.39mA
-586mV    -11.72mA   -6.263mA   -16.71mA
-519mV    -12.9mA    -6.765mA   -18.14mA
-452mV    -20.65mA   -7.381mA   -28.43mA
-385mV    -644.6uA   -10.95mA   -18.39mA
-318mV    -20.45uA   -277.3uA   3.509uA
3.3V      0A         0A         0A
